###############################################################
#  Generated by:      Cadence Innovus 20.13-s083_1
#  OS:                Linux x86_64(Host ID rice-503-20-north)
#  Generated on:      Mon May  9 03:09:54 2022
#  Design:            BGR_Top
#  Command:           write_lef_abstract -5.8 -extractBlockObs /home/users/xingyuni/ee372/aloe-sky130/aloe/layout/output/lef/BGR_V1_1_10.lef
###############################################################

VERSION 5.8 ;

BUSBITCHARS "[]" ;
DIVIDERCHAR "/" ;

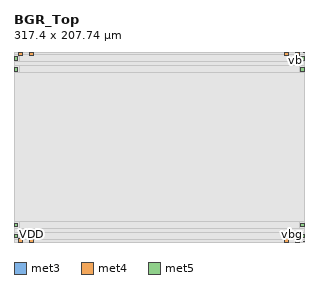
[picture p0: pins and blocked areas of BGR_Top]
MACRO BGR_Top
  CLASS BLOCK ;
  SIZE 317.400000 BY 207.740000 ;
  FOREIGN BGR_Top 0.000000 0.000000 ;
  ORIGIN 0 0 ;
  SYMMETRY X Y R90 ;
  PIN clk
    DIRECTION INPUT ;
    USE SIGNAL ;
  END clk
  PIN porst
    DIRECTION INPUT ;
    USE SIGNAL ;
  END porst
  PIN va
    DIRECTION OUTPUT ;
    USE SIGNAL ;
  END va
  PIN vb
    DIRECTION OUTPUT ;
    USE SIGNAL ;
    PORT
      LAYER met3 ;
        RECT 316.600000 207.310000 317.400000 207.610000 ;
    END
  END vb
  PIN vbg
    DIRECTION OUTPUT ;
    USE SIGNAL ;
    PORT
      LAYER met3 ;
        RECT 316.600000 0.520000 317.400000 0.820000 ;
    END
  END vbg
  PIN VSS
    DIRECTION INOUT ;
    USE GROUND ;
    PORT
      LAYER met4 ;
        RECT 4.980000 0.000000 8.980000 4.000000 ;
    END
    PORT
      LAYER met4 ;
        RECT 4.980000 203.740000 8.980000 207.740000 ;
    END
    PORT
      LAYER met4 ;
        RECT 308.190000 0.000000 312.190000 4.000000 ;
    END
    PORT
      LAYER met4 ;
        RECT 308.190000 203.740000 312.190000 207.740000 ;
    END
    PORT
      LAYER met5 ;
        RECT 0.000000 4.560000 4.000000 8.560000 ;
    END
    PORT
      LAYER met5 ;
        RECT 313.400000 4.560000 317.400000 8.560000 ;
    END
    PORT
      LAYER met5 ;
        RECT 0.000000 198.960000 4.000000 202.960000 ;
    END
    PORT
      LAYER met5 ;
        RECT 313.400000 198.960000 317.400000 202.960000 ;
    END
  END VSS
  PIN VDD
    DIRECTION INOUT ;
    USE POWER ;
    PORT
      LAYER met4 ;
        RECT 16.980000 0.000000 20.980000 4.000000 ;
    END
    PORT
      LAYER met4 ;
        RECT 16.980000 203.740000 20.980000 207.740000 ;
    END
    PORT
      LAYER met4 ;
        RECT 296.190000 0.000000 300.190000 4.000000 ;
    END
    PORT
      LAYER met4 ;
        RECT 296.190000 203.740000 300.190000 207.740000 ;
    END
    PORT
      LAYER met5 ;
        RECT 0.000000 16.560000 4.000000 20.560000 ;
    END
    PORT
      LAYER met5 ;
        RECT 313.400000 16.560000 317.400000 20.560000 ;
    END
    PORT
      LAYER met5 ;
        RECT 0.000000 186.960000 4.000000 190.960000 ;
    END
    PORT
      LAYER met5 ;
        RECT 313.400000 186.960000 317.400000 190.960000 ;
    END
  END VDD
  OBS
    LAYER li1 ;
      RECT 0.000000 0.000000 317.400000 207.740000 ;
    LAYER met1 ;
      RECT 0.000000 0.000000 317.400000 207.740000 ;
    LAYER met2 ;
      RECT 0.000000 0.000000 317.400000 207.740000 ;
    LAYER met3 ;
      RECT 0.000000 206.910000 316.200000 207.740000 ;
      RECT 0.000000 1.220000 317.400000 206.910000 ;
      RECT 0.000000 0.120000 316.200000 1.220000 ;
      RECT 0.000000 0.000000 317.400000 0.120000 ;
    LAYER met4 ;
      RECT 312.590000 203.340000 317.400000 207.740000 ;
      RECT 300.590000 203.340000 307.790000 207.740000 ;
      RECT 21.380000 203.340000 295.790000 207.740000 ;
      RECT 9.380000 203.340000 16.580000 207.740000 ;
      RECT 0.000000 203.340000 4.580000 207.740000 ;
      RECT 0.000000 4.400000 317.400000 203.340000 ;
      RECT 312.590000 0.000000 317.400000 4.400000 ;
      RECT 300.590000 0.000000 307.790000 4.400000 ;
      RECT 21.380000 0.000000 295.790000 4.400000 ;
      RECT 9.380000 0.000000 16.580000 4.400000 ;
      RECT 0.000000 0.000000 4.580000 4.400000 ;
    LAYER met5 ;
      RECT 0.000000 204.560000 317.400000 207.740000 ;
      RECT 5.600000 197.360000 311.800000 204.560000 ;
      RECT 0.000000 192.560000 317.400000 197.360000 ;
      RECT 5.600000 185.360000 311.800000 192.560000 ;
      RECT 0.000000 22.160000 317.400000 185.360000 ;
      RECT 5.600000 14.960000 311.800000 22.160000 ;
      RECT 0.000000 10.160000 317.400000 14.960000 ;
      RECT 5.600000 2.960000 311.800000 10.160000 ;
      RECT 0.000000 0.000000 317.400000 2.960000 ;
  END
END BGR_Top

END LIBRARY
